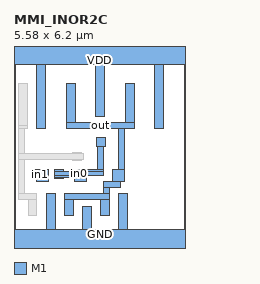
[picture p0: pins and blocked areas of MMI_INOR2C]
MACRO MMI_INOR2C
	CLASS CORE ;
	FOREIGN MMI_INOR2C 0 0 ;
	SIZE 5.58 BY 6.2 ;
	SYMMETRY X Y ;
	SITE CORE1 ;
	PIN out
		DIRECTION output ;
		USE SIGNAL ;
		PORT
			LAYER M1 ;
			RECT 1.715 3.89 1.995 5.165 ;
			LAYER M1 ;
			RECT 3.64 3.89 3.92 5.165 ;
			LAYER M1 ;
			RECT 1.715 3.695 3.92 3.89 ;
			LAYER M1 ;
			RECT 3.4 2.36 3.595 3.695 ;
			LAYER M1 ;
			RECT 3.22 1.98 3.595 2.36 ;
			LAYER M1 ;
			RECT 3.22 1.97 3.47 1.98 ;
			LAYER M1 ;
			RECT 2.925 1.775 3.47 1.97 ;
			LAYER M1 ;
			RECT 2.925 1.575 3.115 1.775 ;
			LAYER M1 ;
			RECT 1.65 1.385 3.115 1.575 ;
			LAYER M1 ;
			RECT 1.65 0.875 1.93 1.385 ;
			LAYER M1 ;
			RECT 2.83 0.875 3.11 1.385 ;
		END
		AntennaDiffArea 2.0328 ;
	END out
	PIN in1
		DIRECTION input ;
		USE SIGNAL ;
		PORT
			LAYER M1 ;
			RECT 0.74 2.35 1.12 2.36 ;
			LAYER M1 ;
			RECT 0.555 2.07 1.12 2.35 ;
			LAYER M1 ;
			RECT 0.74 1.98 1.12 2.07 ;
		END
		AntennaGateArea 0.3465 ;
	END in1
	PIN GND
		DIRECTION inout ;
		USE GROUND ;
		PORT
			LAYER M1 ;
			RECT 1.06 0.42 1.34 1.575 ;
			LAYER M1 ;
			RECT 2.24 0.42 2.52 1.155 ;
			LAYER M1 ;
			RECT 3.42 0.42 3.7 1.575 ;
			LAYER M1 ;
			RECT 0 -0.42 5.58 0.42 ;
		END
	END GND
	PIN VDD
		DIRECTION inout ;
		USE POWER ;
		PORT
			LAYER M1 ;
			RECT 0 5.78 5.58 6.62 ;
			LAYER M1 ;
			RECT 0.75 3.695 1.03 5.78 ;
			LAYER M1 ;
			RECT 2.675 4.105 2.955 5.78 ;
			LAYER M1 ;
			RECT 4.6 3.695 4.88 5.78 ;
		END
	END VDD
	PIN in0
		DIRECTION input ;
		USE SIGNAL ;
		PORT
			LAYER M1 ;
			RECT 2.69 3.125 2.97 3.405 ;
			LAYER M1 ;
			RECT 2.73 2.365 2.92 3.125 ;
			LAYER M1 ;
			RECT 1.32 2.31 1.6 2.35 ;
			LAYER M1 ;
			RECT 1.98 2.31 2.92 2.365 ;
			LAYER M1 ;
			RECT 1.32 2.17 2.92 2.31 ;
			LAYER M1 ;
			RECT 1.32 2.115 2.36 2.17 ;
			LAYER M1 ;
			RECT 1.32 2.07 1.6 2.115 ;
			LAYER M1 ;
			RECT 1.98 1.98 2.36 2.115 ;
		END
		AntennaGateArea 1.155 ;
	END in0
	OBS
		LAYER M1 ;
		RECT 0.16 3.79 0.44 5.165 ;
		LAYER M1 ;
		RECT 0.155 3.695 0.44 3.79 ;
		LAYER M1 ;
		RECT 0.155 2.885 0.35 3.695 ;
		LAYER M1 ;
		RECT 1.92 2.885 2.2 2.93 ;
		LAYER M1 ;
		RECT 0.155 2.695 2.26 2.885 ;
		LAYER M1 ;
		RECT 0.155 1.575 0.35 2.695 ;
		LAYER M1 ;
		RECT 1.92 2.65 2.2 2.695 ;
		LAYER M1 ;
		RECT 0.155 1.385 0.75 1.575 ;
		LAYER M1 ;
		RECT 0.47 0.875 0.75 1.385 ;
	END
END MMI_INOR2C
